(* Logix 5000 AddOnInstructionDefinition export AOI_NTron_7012FX2_v1_2; software revision 20.04; part 2 of 2 *)
(* tags used below, declared in another part *)
   kObjectClassEthernetLink : INT;
   messageCounter : COUNTER;
   messageTimer : TIMER;
   class : INT;
   port : INT;
   kMaxPortNumber : INT;
   index : DINT;
   kAttributeAdminEnable : INT;
   kAttributeSpeedDuplex : INT;
   port_mask2 : DINT;
   port_mask : DINT;
   bRequestData : BOOL;
   bResetCounter : BOOL;
   bSetMessage : BOOL;
   oInterfaceControl : UDT_NTRON_CIP_Interface_Control_v0;
(* AOI_NTron_Common_v1_2, continued *)

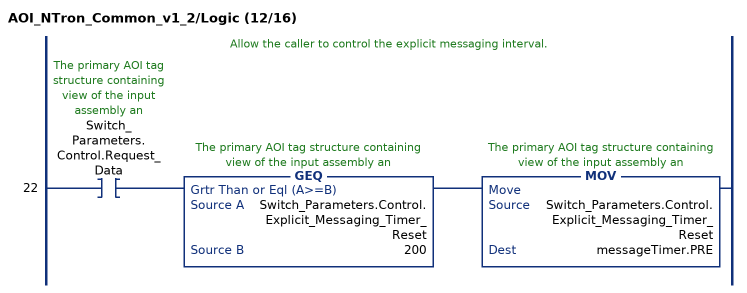
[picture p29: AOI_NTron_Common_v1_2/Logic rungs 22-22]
   // Allow the caller to control the explicit messaging interval.
   22: XIC(Switch_Parameters.Control.Request_Data)GEQ(Switch_Parameters.Control.Explicit_Messaging_Timer_Reset,200)MOV(Switch_Parameters.Control.Explicit_Messaging_Timer_Reset,messageTimer.PRE);
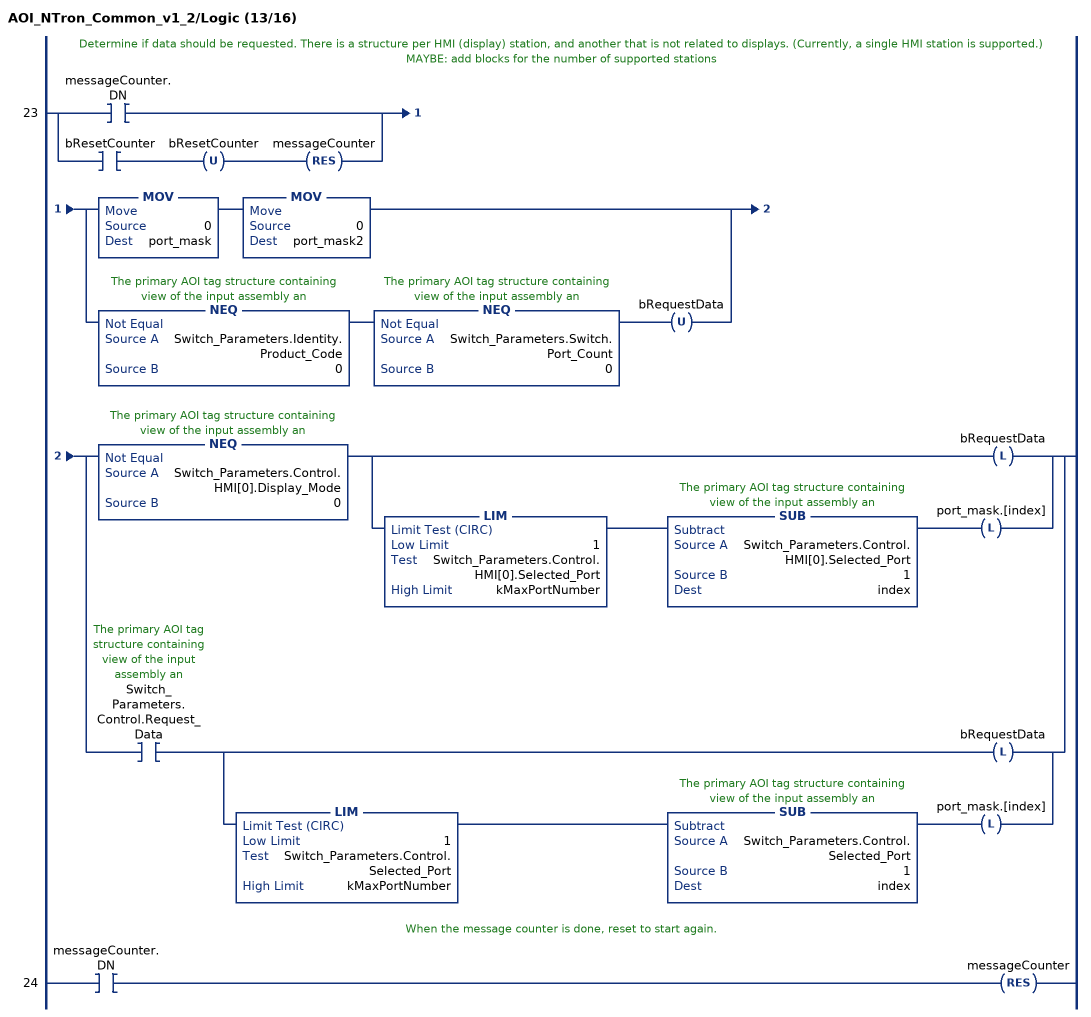
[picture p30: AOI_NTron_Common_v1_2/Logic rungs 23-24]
   // Determine if data should be requested. There is a structure per HMI (display) station, and another that is not related to displays. (Currently, a single HMI station is supported.)
   // MAYBE: add blocks for the number of supported stations
   23: [XIC(messageCounter.DN) ,XIC(bResetCounter) OTU(bResetCounter) RES(messageCounter) ][MOV(0,port_mask) MOV(0,port_mask2) ,NEQ(Switch_Parameters.Identity.Product_Code,0) NEQ(Switch_Parameters.Switch.Port_Count,0) OTU(bRequestData) ][NEQ(Switch_Parameters.Control.HMI[0].Display_Mode,0) [OTL(bRequestData) ,LIM(1,Switch_Parameters.Control.HMI[0].Selected_Port,kMaxPortNumber) SUB(Switch_Parameters.Control.HMI[0].Selected_Port,1,index) OTL(port_mask.[index]) ] ,XIC(Switch_Parameters.Control.Request_Data) [OTL(bRequestData) ,LIM(1,Switch_Parameters.Control.Selected_Port,kMaxPortNumber) SUB(Switch_Parameters.Control.Selected_Port,1,index) OTL(port_mask.[index]) ] ];
   // When the message counter is done, reset to start again.
   24: XIC(messageCounter.DN)RES(messageCounter);
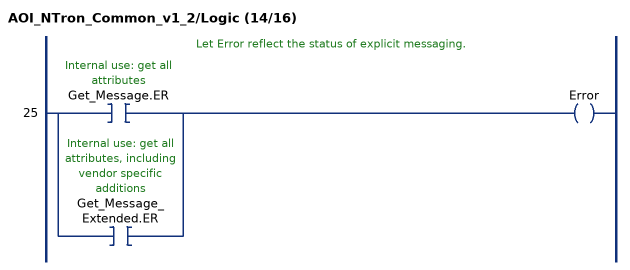
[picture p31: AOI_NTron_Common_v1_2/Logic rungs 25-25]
   // Let Error reflect the status of explicit messaging.
   25: [XIC(Get_Message.ER) ,XIC(Get_Message_Extended.ER) ]OTE(Error);
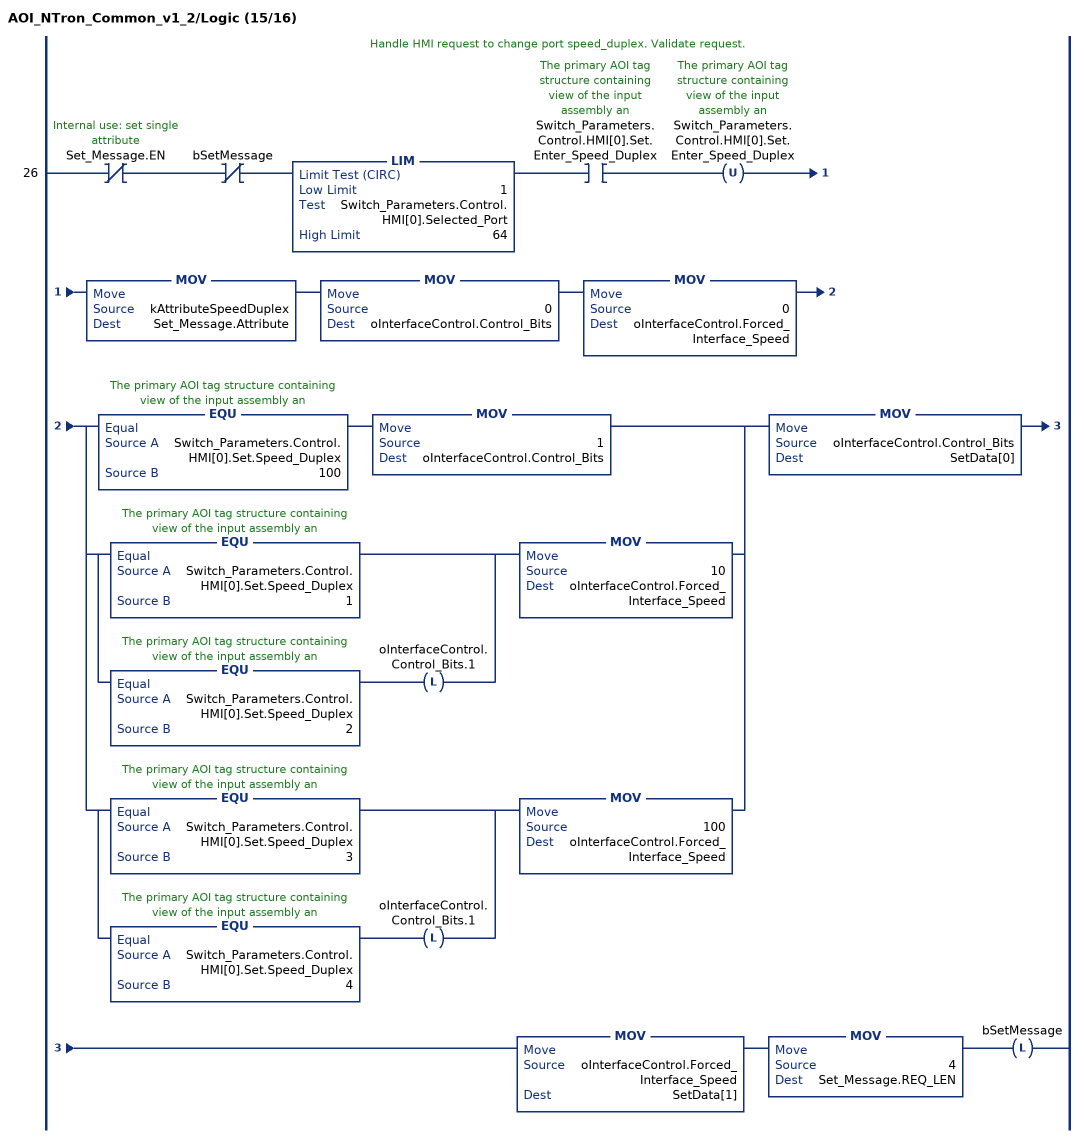
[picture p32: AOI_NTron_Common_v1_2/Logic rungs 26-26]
   // Handle HMI request to change port speed_duplex. Validate request.
   26: XIO(Set_Message.EN)XIO(bSetMessage)LIM(1,Switch_Parameters.Control.HMI[0].Selected_Port,64)XIC(Switch_Parameters.Control.HMI[0].Set.Enter_Speed_Duplex)OTU(Switch_Parameters.Control.HMI[0].Set.Enter_Speed_Duplex)MOV(kAttributeSpeedDuplex,Set_Message.Attribute)MOV(0,oInterfaceControl.Control_Bits)MOV(0,oInterfaceControl.Forced_Interface_Speed)[EQU(Switch_Parameters.Control.HMI[0].Set.Speed_Duplex,100) MOV(1,oInterfaceControl.Control_Bits) ,[EQU(Switch_Parameters.Control.HMI[0].Set.Speed_Duplex,1) ,EQU(Switch_Parameters.Control.HMI[0].Set.Speed_Duplex,2) OTL(oInterfaceControl.Control_Bits.1) ] MOV(10,oInterfaceControl.Forced_Interface_Speed) ,[EQU(Switch_Parameters.Control.HMI[0].Set.Speed_Duplex,3) ,EQU(Switch_Parameters.Control.HMI[0].Set.Speed_Duplex,4) OTL(oInterfaceControl.Control_Bits.1) ] MOV(100,oInterfaceControl.Forced_Interface_Speed) ]MOV(oInterfaceControl.Control_Bits,SetData[0])MOV(oInterfaceControl.Forced_Interface_Speed,SetData[1])MOV(4,Set_Message.REQ_LEN)OTL(bSetMessage);
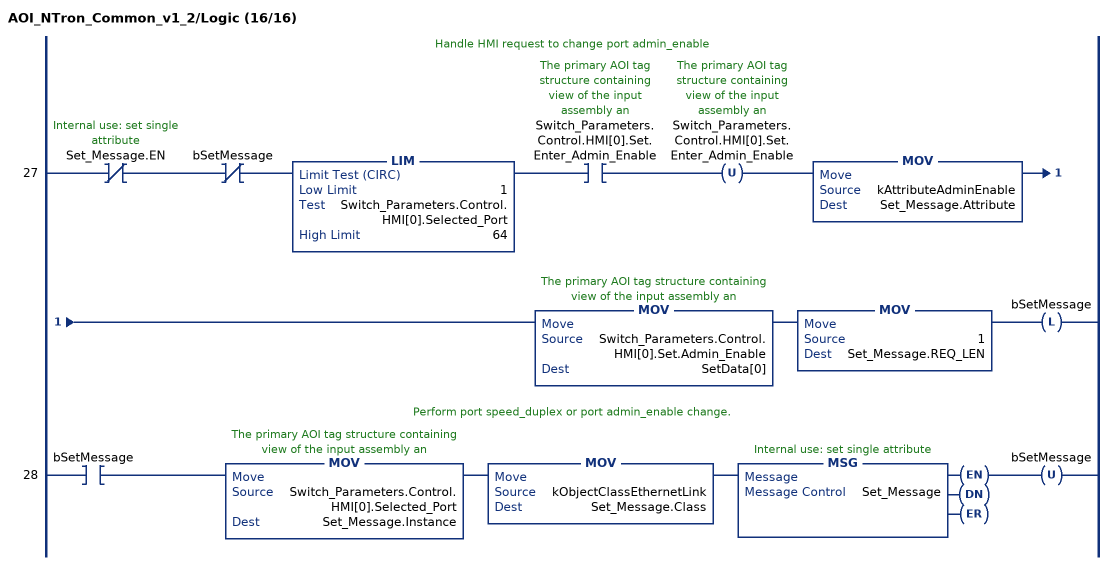
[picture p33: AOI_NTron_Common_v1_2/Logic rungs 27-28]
   // Handle HMI request to change port admin_enable
   27: XIO(Set_Message.EN)XIO(bSetMessage)LIM(1,Switch_Parameters.Control.HMI[0].Selected_Port,64)XIC(Switch_Parameters.Control.HMI[0].Set.Enter_Admin_Enable)OTU(Switch_Parameters.Control.HMI[0].Set.Enter_Admin_Enable)MOV(kAttributeAdminEnable,Set_Message.Attribute)MOV(Switch_Parameters.Control.HMI[0].Set.Admin_Enable,SetData[0])MOV(1,Set_Message.REQ_LEN)OTL(bSetMessage);
   // Perform port speed_duplex or port admin_enable change.
   28: XIC(bSetMessage)MOV(Switch_Parameters.Control.HMI[0].Selected_Port,Set_Message.Instance)MOV(kObjectClassEthernetLink,Set_Message.Class)MSG(Set_Message)OTU(bSetMessage);
END_ROUTINE
END_ADD_ON_INSTRUCTION

ADD_ON_INSTRUCTION AOI_NTron_7012FX2_v1_2   (* revision 1.2 December 2015, vendor Red Lion Controls, Inc. *)
// N-Tron 7012FX2 switch.
// (C) 2015 Red Lion Controls, Inc. All rights reserved.
// Help:
// Refer to the installation document for more details.
VAR_IN_OUT
   Switch_Inputs : DINT[26]; {required}   // The module defined array representing the input assembly
        [5]   // Set utilization alarm flags for first 32 ports
   Switch_Output : DINT[1]; {required}   // The module defined array representing the output assembly
   Switch_Parameters : UDT_NTRON_Switch_Common_v1; {required}   // The primary AOI tag structure containing view of the input assembly and CIP object data
        .DATA.PORT_INTERFACE_TYPE   // Main operand description
   Input_Assembly : UDT_NTRON_Switch_7012FX2_In_v0; {required}   // Input assembly for switch
END_VAR
VAR_OUTPUT
   Error : BOOL; {access Read Only}
END_VAR
VAR_IN_OUT
   Get_Message : MESSAGE; {required}   // Internal use: get all attributes
   Get_Message_Extended : MESSAGE; {required}   // Internal use: get all attributes, including vendor specific additions
   Storage : SINT[1200]; {required}   // Internal use: storage for explicit messaging responses
   Set_Message : MESSAGE; {required}   // Internal use: set single attribute
   SetData : INT[2]; {required}   // Internal use: data for set single attribute
END_VAR
VAR
   copyTimer : TIMER := (PRE := 5000);
   NTRON_common : AOI_NTron_Common_v1_2;
END_VAR

ROUTINE Logic   (* ladder *)
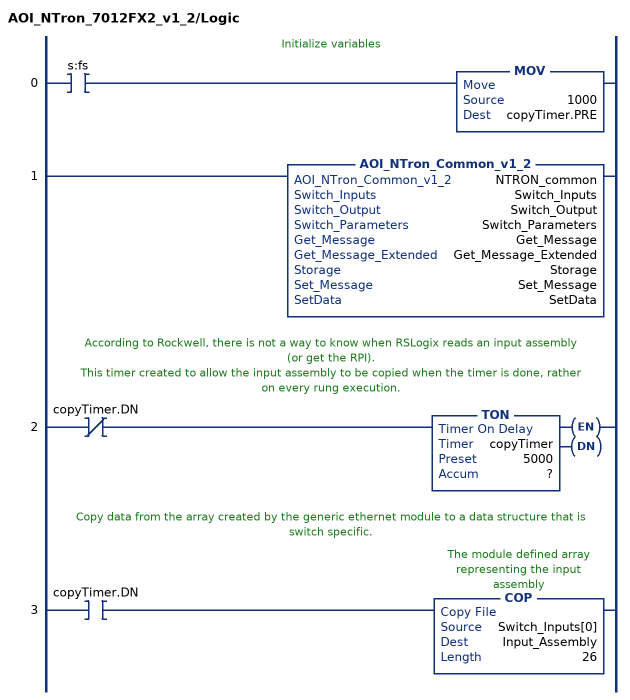
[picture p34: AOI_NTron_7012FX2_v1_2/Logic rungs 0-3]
   // Initialize variables
   0: XIC(s:fs)MOV(1000,copyTimer.PRE);
   1: AOI_NTron_Common_v1_2(NTRON_common,Switch_Inputs,Switch_Output,Switch_Parameters,Get_Message,Get_Message_Extended,Storage,Set_Message,SetData);
   // According to Rockwell, there is not a way to know when RSLogix reads an input assembly (or get the RPI).
   // This timer created to allow the input assembly to be copied when the timer is done, rather on every rung execution.
   2: XIO(copyTimer.DN)TON(copyTimer,?,?);
   // Copy data from the array created by the generic ethernet module to a data structure that is switch specific.
   3: XIC(copyTimer.DN)COP(Switch_Inputs[0],Input_Assembly,26);
END_ROUTINE
END_ADD_ON_INSTRUCTION
